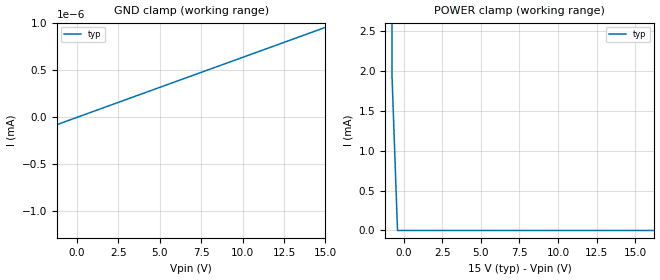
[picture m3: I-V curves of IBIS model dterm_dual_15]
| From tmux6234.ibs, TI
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| dterm_dual_15
[Model]   dterm_dual_15
Model_type   Terminator
|   typ   min   max
C_comp   1.598234e-11   NA   NA
[Voltage Range]   15   NA   NA
[Temperature Range]   27   NA   NA
[Power Clamp Reference]   15   NA   NA
[GND Clamp Reference]   0   NA   NA
[GND Clamp]
|   Voltage   I(typ)   I(min)   I(max)
-20V      -2.37A     NA         NA
-15.4V    -150.4nA   NA         NA
-15.05V   -985.5pA   NA         NA
-14.7V    -955.1pA   NA         NA
15V       958.9pA    NA         NA
[POWER Clamp]
|   Voltage   I(typ)   I(min)   I(max)
-5V       3.079A     NA         NA
-1.111V   98.3mA     NA         NA
-757.6mV  1.926mA    NA         NA
-404mV    185.6nA    NA         NA
30V       -975.9pA   NA         NA
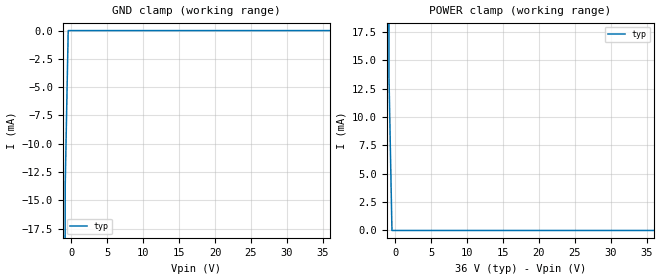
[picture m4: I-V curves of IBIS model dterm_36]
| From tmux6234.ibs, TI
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| dterm_36
[Model]   dterm_36
Model_type   Terminator
|   typ   min   max
C_comp   1.598234e-11   NA   NA
[Voltage Range]   36   NA   NA
[Temperature Range]   27   NA   NA
[Power Clamp Reference]   36   NA   NA
[GND Clamp Reference]   0   NA   NA
[GND Clamp]
|   Voltage   I(typ)   I(min)   I(max)
-5V       -2.38A     NA         NA
-1.273V   -154.4mA   NA         NA
-858.6mV  -13.59mA   NA         NA
-444.4mV  -545.5nA   NA         NA
36V       1.152nA    NA         NA
[POWER Clamp]
|   Voltage   I(typ)   I(min)   I(max)
-5V       3.081A     NA         NA
-1.273V   167.8mA    NA         NA
-858.6mV  13.56mA    NA         NA
-444.4mV  684.9nA    NA         NA
36V       -1.179nA   NA         NA
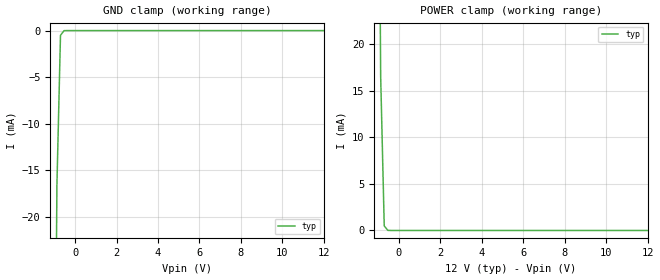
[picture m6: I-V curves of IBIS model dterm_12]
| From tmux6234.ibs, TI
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| dterm_12
[Model]   dterm_12
Model_type   Terminator
|   typ   min   max
C_comp   1.008417e-11   NA   NA
[Voltage Range]   12   NA   NA
[Temperature Range]   27   NA   NA
[Power Clamp Reference]   12   NA   NA
[GND Clamp Reference]   0   NA   NA
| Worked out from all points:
|   GND clamp passes 1 mA (typ) near -0.71 V on its own axis
|   POWER clamp passes 1 mA (typ) near -0.71 V on its own axis
[GND Clamp]
|   Voltage   I(typ)   I(min)   I(max)
-5V       -2.324A    NA         NA
-1.051V   -66mA      NA         NA
-878.8mV  -16.54mA   NA         NA
-707.1mV  -512.4uA   NA         NA
-535.4mV  -9.804uA   NA         NA
12V       382pA      NA         NA
[POWER Clamp]
|   Voltage   I(typ)   I(min)   I(max)
-5V       3.073A     NA         NA
-1.05V    68.78mA    NA         NA
-878.8mV  16.53mA    NA         NA
-707.1mV  492.9uA    NA         NA
-535.4mV  12.29uA    NA         NA
12V       -386.3pA   NA         NA
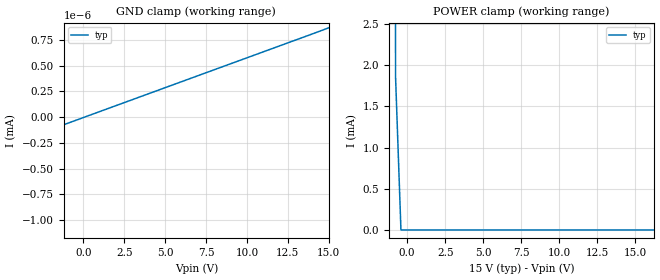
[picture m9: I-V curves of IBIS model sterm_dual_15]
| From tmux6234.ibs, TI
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| sterm_dual_15
[Model]   sterm_dual_15
Model_type   Terminator
|   typ   min   max
C_comp   1.008417e-11   NA   NA
[Voltage Range]   15   NA   NA
[Temperature Range]   27   NA   NA
[Power Clamp Reference]   15   NA   NA
[GND Clamp Reference]   0   NA   NA
[GND Clamp]
|   Voltage   I(typ)   I(min)   I(max)
-20V      -2.144A    NA         NA
-15.4V    -150.4nA   NA         NA
-15.05V   -891.5pA   NA         NA
-14.7V    -863.3pA   NA         NA
15V       866.2pA    NA         NA
[POWER Clamp]
|   Voltage   I(typ)   I(min)   I(max)
-5V       2.76A      NA         NA
-1.111V   81.89mA    NA         NA
-757.6mV  1.856mA    NA         NA
-404mV    185.7nA    NA         NA
30V       -882.1pA   NA         NA
